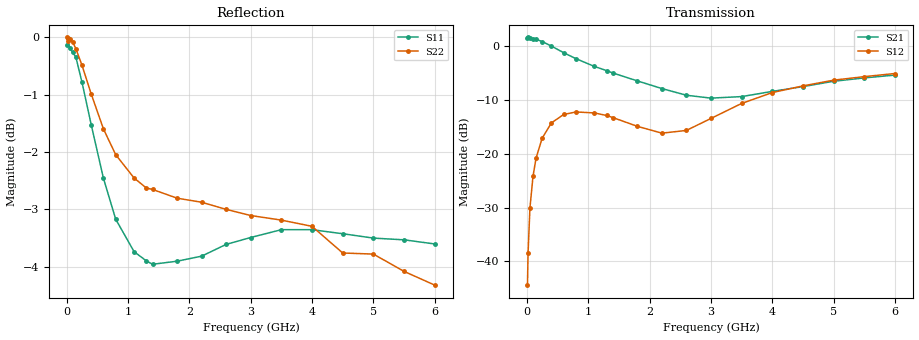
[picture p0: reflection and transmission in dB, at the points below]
! Infineon Technologies  Discrete & RF Semiconductors
! BFS17W
! Si NPN RF Bipolar Junction Transistor in SOT323
! VCE = 1 V  IC = 0.3 mA
! Common Emitter S-Parameters:  August  1999
# GHz  S  MA  R  50
!  f  S11  S21  S12  S22
! GHz  MAG  ANG  MAG  ANG  MAG  ANG  MAG  ANG
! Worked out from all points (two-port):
!   36 points, 10 MHz to 6 GHz, reference 50 ohm
!   highest |S21| = 1.64 dB at 20 MHz (marker M1); lowest = -9.7 dB at 3 GHz (marker M2)
!   |S21| within 3 dB of the highest: start of sweep to 625.3 MHz
!   lowest |S11| = -4.0 dB at 1.4 GHz (marker M3), VSWR 4.46, Z = 11.5 - j8.15 ohm
!   |S11| at or under -10 dB: nowhere
!   |S22| runs from -4.3 to 0.0 dB; largest |S21 - S12| = 1.2
!   S11 on the Smith chart (normalised r, x): 10 MHz: 28, -52; 250 MHz: 0.29, -2.31; 600 MHz: 0.25, -0.86; 1.3 GHz: 0.23, -0.21; 3 GHz: 0.23, +0.39; 6 GHz: 0.47, +1.09
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0.01  0.9843 -1.7  1.19 179.1  0.006 90.2  0.9999 -0.2
0.02  0.9985 -4.0  1.208 176.6  0.012 87.9  0.9926 -1.4
0.05  0.9784 -9.6  1.194 171.3  0.0312 83.9  0.9961 -3.4
0.1  0.9701 -19.1  1.177 163.0  0.0615 77.9  0.9905 -6.9
0.15  0.9612 -29.0  1.162 154.2  0.0912 71.2  0.9775 -10.1
0.25  0.914 -46.3  1.104 138.1  0.1396 60.0  0.9456 -16.1
0.4  0.8394 -70.3  1.003 116.6  0.1935 46.0  0.8927 -23.6
0.6  0.7535 -96.5  0.87 93.8  0.2317 32.0  0.832 -31.3
0.8  0.694 -117.2  0.766 76.3  0.2447 22.1  0.79 -38.2
1.1  0.6502 -141.7  0.649 56.3  0.2396 12.1  0.7539 -47.9
1.3  0.6383 -155.2  0.593 46.4  0.2268 7.8  0.7389 -54.8
1.4  0.634 -160.5  0.564 42.0  0.2172 6.5  0.7368 -58.0
1.8  0.6379 179.2  0.476 28.9  0.18 7.5  0.724 -72.3
2.2  0.6444 162.8  0.404 22.1  0.1554 19.9  0.7181 -86.7
2.6  0.6598 148.3  0.35 21.0  0.1647 38.4  0.7079 -101.5
3  0.669 135.2  0.329 24.9  0.2128 49.4  0.6992 -115.4
3.5  0.6796 120.9  0.34 30.2  0.2935 51.3  0.6928 -132.9
4  0.6796 109.1  0.38 32.3  0.3704 46.5  0.6842 -150.4
4.5  0.6741 98.9  0.421 31.2  0.4275 40.3  0.6485 -165.7
5  0.6682 91.3  0.472 28.0  0.4834 34.2  0.6471 -178.0
5.5  0.6659 84.6  0.507 23.8  0.5213 28.3  0.625 169.0
6  0.6604 79.3  0.539 19.6  0.5572 22.7  0.608 158.0
